# TR-1um フレーム / パッドセルの LEF
# scripts/mkleffrm.py が生成。手で編集しないこと。
# source: TR-1um_frame_25x25.gds

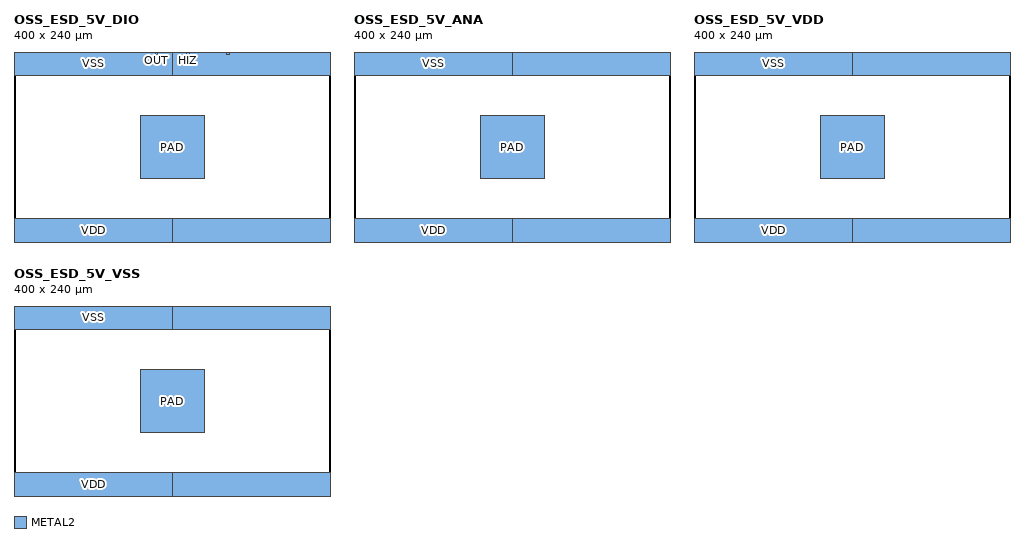
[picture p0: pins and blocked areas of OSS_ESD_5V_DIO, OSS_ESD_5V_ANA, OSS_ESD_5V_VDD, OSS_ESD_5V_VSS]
MACRO OSS_ESD_5V_DIO
  # 3 ステート双方向 IO。HIZ=0 で PAD=OUT（非反転）、HIZ=1 で高Z。
  CLASS PAD ;
  FOREIGN OSS_ESD_5V_DIO 200.000 120.000 ;
  ORIGIN 0.000 0.000 ;
  SIZE 400.000 BY 240.000 ;
  SYMMETRY X Y ;
  PIN HIZ
    DIRECTION INPUT ;
    USE SIGNAL ;
    PORT
      LAYER METAL2 ;
        RECT 218.300 236.600 221.700 240.000 ;
    END
  END HIZ
  PIN OUT
    DIRECTION INPUT ;
    USE SIGNAL ;
    PORT
      LAYER METAL2 ;
        RECT 178.300 236.600 181.700 240.000 ;
    END
  END OUT
  PIN PAD
    DIRECTION INOUT ;
    USE SIGNAL ;
    PORT
      LAYER METAL2 ;
        RECT 268.300 236.600 271.700 240.000 ;
        RECT 160.000 80.000 240.000 160.000 ;
    END
  END PAD
  PIN VDD
    DIRECTION INOUT ;
    USE POWER ;
    SHAPE ABUTMENT ;
    PORT
      LAYER METAL2 ;
        RECT 0.000 0.000 200.000 30.000 ;
        RECT 200.000 0.000 400.000 30.000 ;
    END
  END VDD
  PIN VSS
    DIRECTION INOUT ;
    USE GROUND ;
    SHAPE ABUTMENT ;
    PORT
      LAYER METAL2 ;
        RECT 0.000 210.000 200.000 240.000 ;
        RECT 200.000 210.000 400.000 240.000 ;
    END
  END VSS
END OSS_ESD_5V_DIO

MACRO OSS_ESD_5V_ANA
  # ESD のみ
  CLASS PAD ;
  FOREIGN OSS_ESD_5V_ANA 200.000 120.000 ;
  ORIGIN 0.000 0.000 ;
  SIZE 400.000 BY 240.000 ;
  SYMMETRY X Y ;
  PIN PAD
    DIRECTION INOUT ;
    USE SIGNAL ;
    PORT
      LAYER METAL2 ;
        RECT 160.000 80.000 240.000 160.000 ;
    END
  END PAD
  PIN VDD
    DIRECTION INOUT ;
    USE POWER ;
    SHAPE ABUTMENT ;
    PORT
      LAYER METAL2 ;
        RECT 0.000 0.000 200.000 30.000 ;
        RECT 200.000 0.000 400.000 30.000 ;
    END
  END VDD
  PIN VSS
    DIRECTION INOUT ;
    USE GROUND ;
    SHAPE ABUTMENT ;
    PORT
      LAYER METAL2 ;
        RECT 0.000 210.000 200.000 240.000 ;
        RECT 200.000 210.000 400.000 240.000 ;
    END
  END VSS
END OSS_ESD_5V_ANA

MACRO OSS_ESD_5V_VDD
  # ESD のみ
  CLASS PAD ;
  FOREIGN OSS_ESD_5V_VDD 200.000 120.000 ;
  ORIGIN 0.000 0.000 ;
  SIZE 400.000 BY 240.000 ;
  SYMMETRY X Y ;
  PIN PAD
    DIRECTION INOUT ;
    USE SIGNAL ;
    PORT
      LAYER METAL2 ;
        RECT 160.000 80.000 240.000 160.000 ;
    END
  END PAD
  PIN VDD
    DIRECTION INOUT ;
    USE POWER ;
    SHAPE ABUTMENT ;
    PORT
      LAYER METAL2 ;
        RECT 0.000 0.000 200.000 30.000 ;
        RECT 200.000 0.000 400.000 30.000 ;
    END
  END VDD
  PIN VSS
    DIRECTION INOUT ;
    USE GROUND ;
    SHAPE ABUTMENT ;
    PORT
      LAYER METAL2 ;
        RECT 0.000 210.000 200.000 240.000 ;
        RECT 200.000 210.000 400.000 240.000 ;
    END
  END VSS
END OSS_ESD_5V_VDD

MACRO OSS_ESD_5V_VSS
  # ESD のみ
  CLASS PAD ;
  FOREIGN OSS_ESD_5V_VSS 200.000 120.000 ;
  ORIGIN 0.000 0.000 ;
  SIZE 400.000 BY 240.000 ;
  SYMMETRY X Y ;
  PIN PAD
    DIRECTION INOUT ;
    USE SIGNAL ;
    PORT
      LAYER METAL2 ;
        RECT 160.000 80.000 240.000 160.000 ;
    END
  END PAD
  PIN VDD
    DIRECTION INOUT ;
    USE POWER ;
    SHAPE ABUTMENT ;
    PORT
      LAYER METAL2 ;
        RECT 0.000 0.000 200.000 30.000 ;
        RECT 200.000 0.000 400.000 30.000 ;
    END
  END VDD
  PIN VSS
    DIRECTION INOUT ;
    USE GROUND ;
    SHAPE ABUTMENT ;
    PORT
      LAYER METAL2 ;
        RECT 0.000 210.000 200.000 240.000 ;
        RECT 200.000 210.000 400.000 240.000 ;
    END
  END VSS
END OSS_ESD_5V_VSS

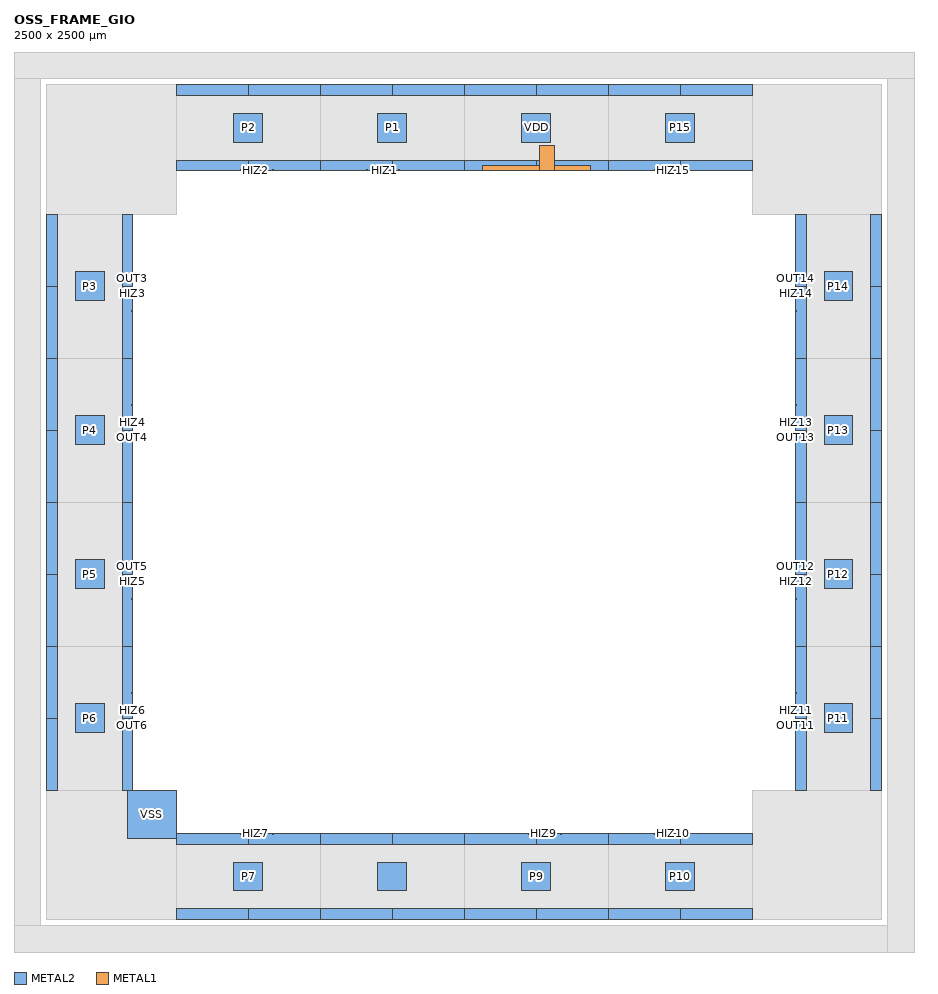
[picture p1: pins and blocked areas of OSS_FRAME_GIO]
MACRO OSS_FRAME_GIO
  # コア: パッド内側 1840 x 1840 um から四隅を欠いて 空き 3.33 mm2 / 内接する最大の正方形 1600 x 1600 um = 2.56 mm2
  CLASS BLOCK ;
  FOREIGN OSS_FRAME_GIO 1250.000 1250.000 ;
  ORIGIN 0.000 0.000 ;
  SIZE 2500.000 BY 2500.000 ;
  SYMMETRY X Y ;
  PIN HIZ1
    DIRECTION INPUT ;
    USE SIGNAL ;
    PORT
      LAYER METAL2 ;
        RECT 1028.300 2170.000 1031.700 2173.400 ;
    END
  END HIZ1
  PIN HIZ10
    DIRECTION INPUT ;
    USE SIGNAL ;
    PORT
      LAYER METAL2 ;
        RECT 1828.300 326.600 1831.700 330.000 ;
    END
  END HIZ10
  PIN HIZ11
    DIRECTION INPUT ;
    USE SIGNAL ;
    PORT
      LAYER METAL2 ;
        RECT 2170.000 668.300 2173.400 671.700 ;
    END
  END HIZ11
  PIN HIZ12
    DIRECTION INPUT ;
    USE SIGNAL ;
    PORT
      LAYER METAL2 ;
        RECT 2170.000 1028.300 2173.400 1031.700 ;
    END
  END HIZ12
  PIN HIZ13
    DIRECTION INPUT ;
    USE SIGNAL ;
    PORT
      LAYER METAL2 ;
        RECT 2170.000 1468.300 2173.400 1471.700 ;
    END
  END HIZ13
  PIN HIZ14
    DIRECTION INPUT ;
    USE SIGNAL ;
    PORT
      LAYER METAL2 ;
        RECT 2170.000 1828.300 2173.400 1831.700 ;
    END
  END HIZ14
  PIN HIZ15
    DIRECTION INPUT ;
    USE SIGNAL ;
    PORT
      LAYER METAL2 ;
        RECT 1828.300 2170.000 1831.700 2173.400 ;
    END
  END HIZ15
  PIN HIZ2
    DIRECTION INPUT ;
    USE SIGNAL ;
    PORT
      LAYER METAL2 ;
        RECT 668.300 2170.000 671.700 2173.400 ;
    END
  END HIZ2
  PIN HIZ3
    DIRECTION INPUT ;
    USE SIGNAL ;
    PORT
      LAYER METAL2 ;
        RECT 326.600 1828.300 330.000 1831.700 ;
    END
  END HIZ3
  PIN HIZ4
    DIRECTION INPUT ;
    USE SIGNAL ;
    PORT
      LAYER METAL2 ;
        RECT 326.600 1468.300 330.000 1471.700 ;
    END
  END HIZ4
  PIN HIZ5
    DIRECTION INPUT ;
    USE SIGNAL ;
    PORT
      LAYER METAL2 ;
        RECT 326.600 1028.300 330.000 1031.700 ;
    END
  END HIZ5
  PIN HIZ6
    DIRECTION INPUT ;
    USE SIGNAL ;
    PORT
      LAYER METAL2 ;
        RECT 326.600 668.300 330.000 671.700 ;
    END
  END HIZ6
  PIN HIZ7
    DIRECTION INPUT ;
    USE SIGNAL ;
    PORT
      LAYER METAL2 ;
        RECT 668.300 326.600 671.700 330.000 ;
    END
  END HIZ7
  PIN HIZ9
    DIRECTION INPUT ;
    USE SIGNAL ;
    PORT
      LAYER METAL2 ;
        RECT 1468.300 326.600 1471.700 330.000 ;
    END
  END HIZ9
  PIN OUT1
    DIRECTION INPUT ;
    USE SIGNAL ;
    PORT
      LAYER METAL2 ;
        RECT 1068.300 2170.000 1071.700 2173.400 ;
    END
  END OUT1
  PIN OUT10
    DIRECTION INPUT ;
    USE SIGNAL ;
    PORT
      LAYER METAL2 ;
        RECT 1868.300 326.600 1871.700 330.000 ;
    END
  END OUT10
  PIN OUT11
    DIRECTION INPUT ;
    USE SIGNAL ;
    PORT
      LAYER METAL2 ;
        RECT 2170.000 628.300 2173.400 631.700 ;
    END
  END OUT11
  PIN OUT12
    DIRECTION INPUT ;
    USE SIGNAL ;
    PORT
      LAYER METAL2 ;
        RECT 2170.000 1068.300 2173.400 1071.700 ;
    END
  END OUT12
  PIN OUT13
    DIRECTION INPUT ;
    USE SIGNAL ;
    PORT
      LAYER METAL2 ;
        RECT 2170.000 1428.300 2173.400 1431.700 ;
    END
  END OUT13
  PIN OUT14
    DIRECTION INPUT ;
    USE SIGNAL ;
    PORT
      LAYER METAL2 ;
        RECT 2170.000 1868.300 2173.400 1871.700 ;
    END
  END OUT14
  PIN OUT15
    DIRECTION INPUT ;
    USE SIGNAL ;
    PORT
      LAYER METAL2 ;
        RECT 1868.300 2170.000 1871.700 2173.400 ;
    END
  END OUT15
  PIN OUT2
    DIRECTION INPUT ;
    USE SIGNAL ;
    PORT
      LAYER METAL2 ;
        RECT 628.300 2170.000 631.700 2173.400 ;
    END
  END OUT2
  PIN OUT3
    DIRECTION INPUT ;
    USE SIGNAL ;
    PORT
      LAYER METAL2 ;
        RECT 326.600 1868.300 330.000 1871.700 ;
    END
  END OUT3
  PIN OUT4
    DIRECTION INPUT ;
    USE SIGNAL ;
    PORT
      LAYER METAL2 ;
        RECT 326.600 1428.300 330.000 1431.700 ;
    END
  END OUT4
  PIN OUT5
    DIRECTION INPUT ;
    USE SIGNAL ;
    PORT
      LAYER METAL2 ;
        RECT 326.600 1068.300 330.000 1071.700 ;
    END
  END OUT5
  PIN OUT6
    DIRECTION INPUT ;
    USE SIGNAL ;
    PORT
      LAYER METAL2 ;
        RECT 326.600 628.300 330.000 631.700 ;
    END
  END OUT6
  PIN OUT7
    DIRECTION INPUT ;
    USE SIGNAL ;
    PORT
      LAYER METAL2 ;
        RECT 628.300 326.600 631.700 330.000 ;
    END
  END OUT7
  PIN OUT9
    DIRECTION INPUT ;
    USE SIGNAL ;
    PORT
      LAYER METAL2 ;
        RECT 1428.300 326.600 1431.700 330.000 ;
    END
  END OUT9
  PIN P1
    DIRECTION INOUT ;
    USE SIGNAL ;
    PORT
      LAYER METAL2 ;
        RECT 978.300 2170.000 981.700 2173.400 ;
        RECT 1010.000 2250.000 1090.000 2330.000 ;
    END
  END P1
  PIN P10
    DIRECTION INOUT ;
    USE SIGNAL ;
    PORT
      LAYER METAL2 ;
        RECT 1778.300 326.600 1781.700 330.000 ;
        RECT 1810.000 170.000 1890.000 250.000 ;
    END
  END P10
  PIN P11
    DIRECTION INOUT ;
    USE SIGNAL ;
    PORT
      LAYER METAL2 ;
        RECT 2170.000 718.300 2173.400 721.700 ;
        RECT 2250.000 610.000 2330.000 690.000 ;
    END
  END P11
  PIN P12
    DIRECTION INOUT ;
    USE SIGNAL ;
    PORT
      LAYER METAL2 ;
        RECT 2170.000 978.300 2173.400 981.700 ;
        RECT 2250.000 1010.000 2330.000 1090.000 ;
    END
  END P12
  PIN P13
    DIRECTION INOUT ;
    USE SIGNAL ;
    PORT
      LAYER METAL2 ;
        RECT 2170.000 1518.300 2173.400 1521.700 ;
        RECT 2250.000 1410.000 2330.000 1490.000 ;
    END
  END P13
  PIN P14
    DIRECTION INOUT ;
    USE SIGNAL ;
    PORT
      LAYER METAL2 ;
        RECT 2170.000 1778.300 2173.400 1781.700 ;
        RECT 2250.000 1810.000 2330.000 1890.000 ;
    END
  END P14
  PIN P15
    DIRECTION INOUT ;
    USE SIGNAL ;
    PORT
      LAYER METAL2 ;
        RECT 1778.300 2170.000 1781.700 2173.400 ;
        RECT 1810.000 2250.000 1890.000 2330.000 ;
    END
  END P15
  PIN P2
    DIRECTION INOUT ;
    USE SIGNAL ;
    PORT
      LAYER METAL2 ;
        RECT 718.300 2170.000 721.700 2173.400 ;
        RECT 610.000 2250.000 690.000 2330.000 ;
    END
  END P2
  PIN P3
    DIRECTION INOUT ;
    USE SIGNAL ;
    PORT
      LAYER METAL2 ;
        RECT 326.600 1778.300 330.000 1781.700 ;
        RECT 170.000 1810.000 250.000 1890.000 ;
    END
  END P3
  PIN P4
    DIRECTION INOUT ;
    USE SIGNAL ;
    PORT
      LAYER METAL2 ;
        RECT 326.600 1518.300 330.000 1521.700 ;
        RECT 170.000 1410.000 250.000 1490.000 ;
    END
  END P4
  PIN P5
    DIRECTION INOUT ;
    USE SIGNAL ;
    PORT
      LAYER METAL2 ;
        RECT 326.600 978.300 330.000 981.700 ;
        RECT 170.000 1010.000 250.000 1090.000 ;
    END
  END P5
  PIN P6
    DIRECTION INOUT ;
    USE SIGNAL ;
    PORT
      LAYER METAL2 ;
        RECT 326.600 718.300 330.000 721.700 ;
        RECT 170.000 610.000 250.000 690.000 ;
    END
  END P6
  PIN P7
    DIRECTION INOUT ;
    USE SIGNAL ;
    PORT
      LAYER METAL2 ;
        RECT 718.300 326.600 721.700 330.000 ;
        RECT 610.000 170.000 690.000 250.000 ;
    END
  END P7
  PIN P9
    DIRECTION INOUT ;
    USE SIGNAL ;
    PORT
      LAYER METAL2 ;
        RECT 1518.300 326.600 1521.700 330.000 ;
        RECT 1410.000 170.000 1490.000 250.000 ;
    END
  END P9
  PIN VDD
    DIRECTION INOUT ;
    USE POWER ;
    SHAPE ABUTMENT ;
    PORT
      LAYER METAL1 ;
        RECT 1460.000 2170.000 1500.000 2240.000 ;
        RECT 1300.000 2170.000 1600.000 2184.000 ;
      LAYER METAL2 ;
        RECT 1410.000 2250.000 1490.000 2330.000 ;
        RECT 90.000 450.000 120.000 650.000 ;
        RECT 90.000 650.000 120.000 850.000 ;
        RECT 90.000 1250.000 120.000 1450.000 ;
        RECT 90.000 1450.000 120.000 1650.000 ;
        RECT 90.000 1050.000 120.000 1250.000 ;
        RECT 90.000 850.000 120.000 1050.000 ;
        RECT 1250.000 90.000 1450.000 120.000 ;
        RECT 1450.000 90.000 1650.000 120.000 ;
        RECT 450.000 90.000 650.000 120.000 ;
        RECT 650.000 90.000 850.000 120.000 ;
        RECT 1050.000 90.000 1250.000 120.000 ;
        RECT 850.000 90.000 1050.000 120.000 ;
        RECT 1850.000 90.000 2050.000 120.000 ;
        RECT 1650.000 90.000 1850.000 120.000 ;
        RECT 2380.000 1850.000 2410.000 2050.000 ;
        RECT 2380.000 1650.000 2410.000 1850.000 ;
        RECT 2380.000 1050.000 2410.000 1250.000 ;
        RECT 2380.000 850.000 2410.000 1050.000 ;
        RECT 2380.000 450.000 2410.000 650.000 ;
        RECT 2380.000 650.000 2410.000 850.000 ;
        RECT 2380.000 1250.000 2410.000 1450.000 ;
        RECT 2380.000 1450.000 2410.000 1650.000 ;
        RECT 1050.000 2380.000 1250.000 2410.000 ;
        RECT 850.000 2380.000 1050.000 2410.000 ;
        RECT 1850.000 2380.000 2050.000 2410.000 ;
        RECT 1650.000 2380.000 1850.000 2410.000 ;
        RECT 1250.000 2380.000 1450.000 2410.000 ;
        RECT 1450.000 2380.000 1650.000 2410.000 ;
        RECT 450.000 2380.000 650.000 2410.000 ;
        RECT 650.000 2380.000 850.000 2410.000 ;
        RECT 90.000 1850.000 120.000 2050.000 ;
        RECT 90.000 1650.000 120.000 1850.000 ;
    END
  END VDD
  PIN VSS
    DIRECTION INOUT ;
    USE GROUND ;
    SHAPE ABUTMENT ;
    PORT
      LAYER METAL2 ;
        RECT 850.000 2170.000 1050.000 2200.000 ;
        RECT 650.000 2170.000 850.000 2200.000 ;
        RECT 1250.000 2170.000 1450.000 2200.000 ;
        RECT 1450.000 2170.000 1650.000 2200.000 ;
        RECT 1850.000 2170.000 2050.000 2200.000 ;
        RECT 300.000 1450.000 330.000 1650.000 ;
        RECT 300.000 1650.000 330.000 1850.000 ;
        RECT 300.000 1250.000 330.000 1450.000 ;
        RECT 300.000 650.000 330.000 850.000 ;
        RECT 300.000 850.000 330.000 1050.000 ;
        RECT 316.000 316.000 450.000 450.000 ;
        RECT 450.000 300.000 650.000 330.000 ;
        RECT 1050.000 300.000 1250.000 330.000 ;
        RECT 850.000 300.000 1050.000 330.000 ;
        RECT 1450.000 300.000 1650.000 330.000 ;
        RECT 1650.000 300.000 1850.000 330.000 ;
        RECT 1850.000 300.000 2050.000 330.000 ;
        RECT 2170.000 850.000 2200.000 1050.000 ;
        RECT 2170.000 650.000 2200.000 850.000 ;
        RECT 2170.000 1050.000 2200.000 1250.000 ;
        RECT 2170.000 1250.000 2200.000 1450.000 ;
        RECT 2170.000 1650.000 2200.000 1850.000 ;
        RECT 2170.000 1450.000 2200.000 1650.000 ;
        RECT 450.000 2170.000 650.000 2200.000 ;
        RECT 1010.000 170.000 1090.000 250.000 ;
        RECT 300.000 450.000 330.000 650.000 ;
        RECT 300.000 1050.000 330.000 1250.000 ;
        RECT 1250.000 300.000 1450.000 330.000 ;
        RECT 650.000 300.000 850.000 330.000 ;
        RECT 2170.000 1850.000 2200.000 2050.000 ;
        RECT 2170.000 450.000 2200.000 650.000 ;
        RECT 1050.000 2170.000 1250.000 2200.000 ;
        RECT 1650.000 2170.000 1850.000 2200.000 ;
        RECT 300.000 1850.000 330.000 2050.000 ;
    END
  END VSS
  OBS
    LAYER METAL1 ;
      RECT 120.000 120.000 320.000 320.000 ;
      RECT 90.000 90.000 450.000 450.000 ;
      RECT 2050.000 90.000 2410.000 450.000 ;
      RECT 90.000 450.000 330.000 850.000 ;
      RECT 90.000 1250.000 330.000 1650.000 ;
      RECT 90.000 850.000 330.000 1250.000 ;
      RECT 1250.000 90.000 1650.000 330.000 ;
      RECT 450.000 90.000 850.000 330.000 ;
      RECT 850.000 90.000 1250.000 330.000 ;
      RECT 1650.000 90.000 2050.000 330.000 ;
      RECT 2170.000 1650.000 2410.000 2050.000 ;
      RECT 2170.000 850.000 2410.000 1250.000 ;
      RECT 2170.000 450.000 2410.000 850.000 ;
      RECT 2170.000 1250.000 2410.000 1650.000 ;
      RECT 850.000 2170.000 1250.000 2410.000 ;
      RECT 1650.000 2170.000 2050.000 2410.000 ;
      RECT 1250.000 2170.000 1650.000 2410.000 ;
      RECT 450.000 2170.000 850.000 2410.000 ;
      RECT 2050.000 2050.000 2410.000 2410.000 ;
      RECT 90.000 2050.000 450.000 2410.000 ;
      RECT 0.000 0.000 73.600 2500.000 ;
      RECT 0.000 0.000 2500.000 73.600 ;
      RECT 2426.400 0.000 2500.000 2500.000 ;
      RECT 0.000 2426.400 2500.000 2500.000 ;
      RECT 90.000 1650.000 330.000 2050.000 ;
    LAYER METAL2 ;
      RECT 120.000 120.000 320.000 320.000 ;
      RECT 90.000 90.000 450.000 450.000 ;
      RECT 2050.000 90.000 2410.000 450.000 ;
      RECT 90.000 450.000 330.000 850.000 ;
      RECT 90.000 1250.000 330.000 1650.000 ;
      RECT 90.000 850.000 330.000 1250.000 ;
      RECT 1250.000 90.000 1650.000 330.000 ;
      RECT 450.000 90.000 850.000 330.000 ;
      RECT 850.000 90.000 1250.000 330.000 ;
      RECT 1650.000 90.000 2050.000 330.000 ;
      RECT 2170.000 1650.000 2410.000 2050.000 ;
      RECT 2170.000 850.000 2410.000 1250.000 ;
      RECT 2170.000 450.000 2410.000 850.000 ;
      RECT 2170.000 1250.000 2410.000 1650.000 ;
      RECT 850.000 2170.000 1250.000 2410.000 ;
      RECT 1650.000 2170.000 2050.000 2410.000 ;
      RECT 1250.000 2170.000 1650.000 2410.000 ;
      RECT 450.000 2170.000 850.000 2410.000 ;
      RECT 2050.000 2050.000 2410.000 2410.000 ;
      RECT 90.000 2050.000 450.000 2410.000 ;
      RECT 0.000 0.000 73.600 2500.000 ;
      RECT 0.000 0.000 2500.000 73.600 ;
      RECT 2426.400 0.000 2500.000 2500.000 ;
      RECT 0.000 2426.400 2500.000 2500.000 ;
      RECT 90.000 1650.000 330.000 2050.000 ;
  END
END OSS_FRAME_GIO
